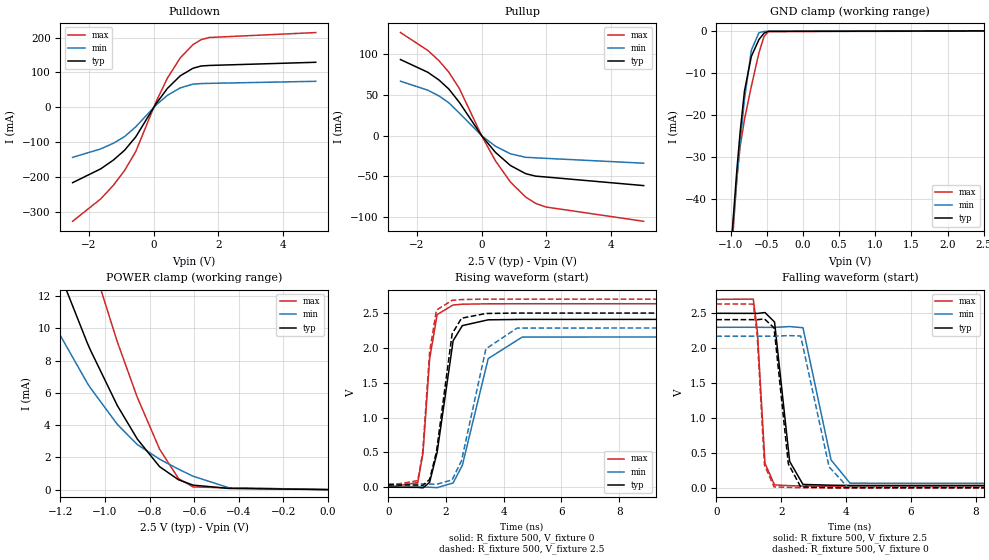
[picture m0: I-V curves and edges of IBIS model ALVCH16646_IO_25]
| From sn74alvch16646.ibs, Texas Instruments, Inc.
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[Model]   ALVCH16646_IO_25
Model_type  I/O
Vinl=0.7
Vinh=1.7
Enable   Active-Low
Vref =   0
Rref =   500
Cref =   30p
Vmeas =   1.25
| variable   typ   min   max
C_comp   8.78pF   7.66pF   9.73pF
| C_pullup   9.93pF   8.26pF   10.92pF
| C_pulldown   13.09pF   9.52pF   17.04pF
| C_tri-state   8.78pF   7.66pF   9.73pF
[Temperature Range]   40   100   -40
| Ambient temperature   25   85   -40
[Voltage range]   2.5   2.3   2.7
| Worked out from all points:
|   slope of the pulldown table from 0 to 0.375 V, typ, clamps not added: 7.66 ohm
|   slope of the pullup table from 0 to 0.375 V, typ, clamps not added: 20.6 ohm
|   GND clamp passes 1 mA (typ) near -0.57 V on its own axis
|   POWER clamp passes 1 mA (typ) near -0.72 V on its own axis
|   rising waveform, R_fixture 500, V_fixture 0: 20-80 % time 455ps typ, 715ps min, 290ps max; typ from 0 V to 2.41 V
|   falling waveform, R_fixture 500, V_fixture 2.5: 20-80 % time 302ps typ, 501ps min, 182ps max; typ from 2.5 V to 0.034 V
|   rising waveform, R_fixture 500, V_fixture 2.5: 20-80 % time 425ps typ, 656ps min, 282ps max; typ from 0.034 V to 2.5 V
|   falling waveform, R_fixture 500, V_fixture 0: 20-80 % time 283ps typ, 486ps min, 176ps max; typ from 2.41 V to 0 V
[GND Clamp]
| ALVCH16646_IO_25
|   Voltage   I(typ)   I(min)   I(max)
-2.5V     -463.5mA   -424.7mA   -524.1mA
-1.085V   -72.18mA   -71.04mA   -77.61mA
-1.065V   -67.29mA   -66.6mA    -72.07mA
-1.05V    -63.66mA   -63.3mA    -67.97mA
-915mV    -32.94mA   -35.07mA   -34.9mA
-870mV    -24.02mA   -26.5mA    -27.39mA
-810mV    -14.27mA   -16.21mA   -21mA
-715mV    -6.042mA   -4.584mA   -13.14mA
-610mV    -2.066mA   -435.3uA   -5.208mA
-540mV    -534.1uA   -124.2uA   -1.331mA
-480mV    -113uA     -83.4uA    -159.8uA
2.5V      87.97pA    20.8uA     -42.68uA
[POWER Clamp]
| ALVCH16646_IO_25
|   Voltage   I(typ)   I(min)   I(max)
-2.5V     78.71mA    58.49mA    109mA
-1.385V   20.48mA    14.69mA    31.36mA
-1.24V    14.7mA     10.52mA    23.24mA
-1.08V    9.114mA    6.62mA     15.15mA
-1.065V   8.641mA    6.299mA    14.44mA
-945mV    5.218mA    4.051mA    9.173mA
-855mV    3.133mA    2.791mA    5.716mA
-755mV    1.42mA     1.885mA    2.505mA
-670mV    609.2uA    1.265mA    681.5uA
-605mV    277uA      830.7uA    166.5uA
-445mV    73.42uA    118.1uA    104.1uA
-31.15fV  87.97pA    322.4pA    50.89pA
[Pulldown]
| ALVCH16646_IO_25
|   Voltage   I(typ)   I(min)   I(max)
-2.5V     -215.2mA   -142.8mA   -325.7mA
-1.635V   -175.8mA   -118.7mA   -261.9mA
-1.24V    -150.4mA   -102.3mA   -222.4mA
-895mV    -122.3mA   -83.19mA   -180.2mA
-550mV    -83.96mA   -55.21mA   -125.8mA
70mV      10.13mA    6.566mA    15.4mA
425mV     54.54mA    34.7mA     83.99mA
820mV     90.47mA    55.98mA    141.7mA
1.215V    112.2mA    66.71mA    179.9mA
1.465V    118.6mA    68.28mA    193.9mA
1.715V    120.1mA    68.87mA    200.1mA
5V        129.2mA    74.77mA    214.2mA
[Pullup]
| ALVCH16646_IO_25
|   Voltage   I(typ)   I(min)   I(max)
-2.5V     92.96mA    66.45mA    126mA
-1.66V    77.48mA    55.56mA    104.2mA
-1.315V   68.02mA    48.56mA    91.64mA
-1.01V    56.98mA    40.11mA    77.55mA
-685mV    40.61mA    27.47mA    57.59mA
15mV      -812.9uA   -531.7uA   -1.2mA
425mV     -20.36mA   -12.93mA   -30.68mA
890mV     -36.57mA   -22.24mA   -56.75mA
1.36V     -46.54mA   -26.55mA   -75.17mA
1.67V     -49.6mA    -27.19mA   -82.95mA
1.985V    -50.63mA   -27.82mA   -87.32mA
5V        -61.14mA   -33.76mA   -104.8mA
[Ramp]
| ALVCH16646_IO_25
| variable   typ   min   max
dV/dt_r   1.45/4.71E-10   1.31/7.46E-10   1.59/3.02E-10
dV/dt_f   1.50/3.25E-10   1.37/5.36E-10   1.62/1.88E-10
R_load = 500
[Rising Waveform]
| ALVCH16646_IO_25
R_fixture =   500
C_fixture =   0
L_fixture =   0
V_fixture =   0
V_fixture_min = 0
V_fixture_max = 0
|   Time   V(typ)   V(min)   V(max)
0s        28.15uV    61.98uV    14.35uV
1.02ns    -2.027mV   1.242mV    67.66mV
1.2ns     -9.088mV   1.562mV    493mV
1.43ns    71.39mV    -361.3uV   1.84V
1.69ns    501mV      -5.697mV   2.478V
2.245ns   2.103V     61.29mV    2.616V
2.565ns   2.32V      316.2mV    2.627V
3.46ns    2.403V     1.846V     2.633V
4.635ns   2.409V     2.155V     2.634V
49.99ns   2.409V     2.172V     2.633V
[Falling Waveform]
| ALVCH16646_IO_25
R_fixture =   500
C_fixture =   0
L_fixture =   0
V_fixture =   2.5
V_fixture_min = 2.3
V_fixture_max = 2.7
|   Time   V(typ)   V(min)   V(max)
0s        2.5V       2.3V       2.7V
1.14ns    2.499V     2.3V       2.703V
1.265ns   2.498V     2.3V       2.25V
1.5ns     2.511V     2.299V     351.5mV
1.795ns   2.375V     2.298V     41.61mV
2.26ns    379mV      2.31V      31.5mV
2.67ns    49.29mV    2.294V     26.35mV
3.535ns   37.82mV    400.8mV    24.2mV
4.12ns    34.7mV     66.68mV    24.02mV
49.99ns   33.75mV    47.74mV    24.02mV
[Rising Waveform]
| ALVCH16646_IO_25
R_fixture =   500
C_fixture =   0
L_fixture =   0
V_fixture =   2.5
V_fixture_min = 2.3
V_fixture_max = 2.7
|   Time   V(typ)   V(min)   V(max)
0s        33.68mV    47.62mV    23.97mV
1.02ns    30.83mV    48.2mV     94.68mV
1.19ns    25.06mV    48.07mV    500.9mV
1.43ns    111.6mV    45.63mV    1.942V
1.665ns   505.5mV    41.32mV    2.542V
2.21ns    2.202V     105.2mV    2.683V
2.535ns   2.426V     381.1mV    2.694V
3.38ns    2.494V     1.986V     2.7V
4.46ns    2.5V       2.284V     2.7V
49.99ns   2.5V       2.3V       2.7V
[Falling Waveform]
| ALVCH16646_IO_25
R_fixture =   500
C_fixture =   0
L_fixture =   0
V_fixture =   0
V_fixture_min = 0
V_fixture_max = 0
|   Time   V(typ)   V(min)   V(max)
0s        2.409V     2.172V     2.633V
1.14ns    2.409V     2.172V     2.632V
1.26ns    2.408V     2.172V     2.188V
1.485ns   2.419V     2.172V     327.1mV
1.78ns    2.292V     2.172V     14.05mV
2.22ns    343.3mV    2.181V     7.067mV
2.6ns     14.18mV    2.175V     2.387mV
3.475ns   3.558mV    300.9mV    185.3uV
4.045ns   947.8uV    11.58mV    29.07uV
49.99ns   34.81uV    75.69uV    18.23uV
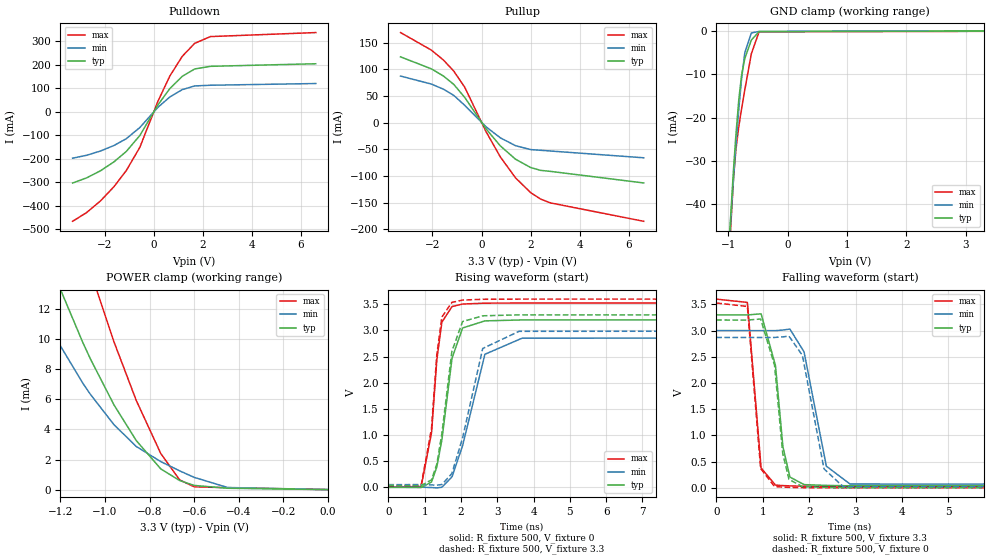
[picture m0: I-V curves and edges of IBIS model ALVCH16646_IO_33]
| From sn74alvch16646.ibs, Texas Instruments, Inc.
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[Model]   ALVCH16646_IO_33
Model_type  I/O
Vinl=0.8
Vinh=2.0
Enable   Active-Low
Vref =   0
Rref =   500
Cref =   50p
Vmeas =   1.5
| variable   typ   min   max
C_comp   8.55pF   7.36pF   9.71pF
| C_pullup   9.73pF   7.94pF   10.64pF
| C_pulldown   12.77pF   8.48pF   17.15pF
| C_tri-state   8.55pF   7.36pF   9.71pF
[Temperature Range]   40   100   -40
| Ambient temperature   25   85   -40
[Voltage range]   3.3   3   3.6
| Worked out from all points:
|   slope of the pulldown table from 0 to 0.495 V, typ, clamps not added: 6.36 ohm
|   slope of the pullup table from 0 to 0.495 V, typ, clamps not added: 16.5 ohm
|   GND clamp passes 1 mA (typ) near -0.56 V on its own axis
|   POWER clamp passes 1 mA (typ) near -0.72 V on its own axis
|   rising waveform, R_fixture 500, V_fixture 0: 20-80 % time 366ps typ, 530ps min, 252ps max; typ from 0 V to 3.2 V
|   falling waveform, R_fixture 500, V_fixture 3.3: 20-80 % time 216ps typ, 352ps min, 150ps max; typ from 3.3 V to 0.037 V
|   rising waveform, R_fixture 500, V_fixture 3.3: 20-80 % time 357ps typ, 504ps min, 249ps max; typ from 0.037 V to 3.3 V
|   falling waveform, R_fixture 500, V_fixture 0: 20-80 % time 208ps typ, 335ps min, 147ps max; typ from 3.2 V to 0 V
[GND Clamp]
| ALVCH16646_IO_33
|   Voltage   I(typ)   I(min)   I(max)
-3.3V     -697.1mA   -635.6mA   -790.9mA
-1.08V    -71.01mA   -69.96mA   -76.29mA
-1.06V    -66.13mA   -65.53mA   -70.76mA
-1.04V    -61.3mA    -61.15mA   -65.33mA
-910mV    -31.95mA   -34.12mA   -33.99mA
-870mV    -24.06mA   -26.53mA   -27.45mA
-820mV    -15.7mA    -17.84mA   -21.96mA
-775mV    -10.28mA   -11.12mA   -18.04mA
-720mV    -6.339mA   -5.024mA   -13.58mA
-610mV    -2.096mA   -458uA     -5.25mA
-480mV    -137.7uA   -101.7uA   -193.7uA
3.3V      119.8pA    41.63uA    -79.23uA
[POWER Clamp]
| ALVCH16646_IO_33
|   Voltage   I(typ)   I(min)   I(max)
-3.3V     128.4mA    96.51mA    173.7mA
-1.385V   20.52mA    14.71mA    31.41mA
-1.235V   14.54mA    10.41mA    23.02mA
-1.1V     9.791mA    7.084mA    16.15mA
-1.065V   8.672mA    6.321mA    14.48mA
-960mV    5.636mA    4.319mA    9.831mA
-860mV    3.263mA    2.869mA    5.931mA
-750mV    1.378mA    1.864mA    2.4mA
-665mV    600.8uA    1.246mA    642.9uA
-600mV    278.6uA    814uA      185.8uA
-450mV    90.53uA    139.8uA    126uA
-48.03fV  119.8pA    365.7pA    68.2pA
[Pulldown]
| ALVCH16646_IO_33
|   Voltage   I(typ)   I(min)   I(max)
-3.3V     -302.9mA   -197.2mA   -465.9mA
-2.735V   -281.2mA   -184.9mA   -429mA
-2.165V   -250.8mA   -166.7mA   -379.1mA
-1.615V   -212.7mA   -143mA     -318.3mA
-1.115V   -168.5mA   -114.3mA   -249.9mA
-565mV    -100.8mA   -66.68mA   -151.3mA
180mV     30.62mA    19.99mA    46.54mA
660mV     99.39mA    63.73mA    152.9mA
1.165V    151.5mA    94.78mA    236.7mA
1.67V     182.8mA    110.5mA    291.9mA
2.31V     194mA      113.5mA    320.7mA
6.6V      205mA      120.8mA    337.8mA
[Pullup]
| ALVCH16646_IO_33
|   Voltage   I(typ)   I(min)   I(max)
-3.3V     123.5mA    87.44mA    169.1mA
-2.045V   101mA      72.4mA     136.2mA
-1.55V    87.39mA    62.74mA    117.4mA
-1.13V    71.66mA    51.07mA    96.68mA
-685mV    47.27mA    32.42mA    66.38mA
180mV     -11.59mA   -7.766mA   -16.76mA
760mV     -43.54mA   -28.44mA   -64.12mA
1.38V     -68.63mA   -43.29mA   -103.6mA
2V        -84.39mA   -50.65mA   -131.6mA
2.405V    -89.66mA   -51.96mA   -143.6mA
2.81V     -91.58mA   -53.32mA   -150.8mA
6.6V      -113.3mA   -66.05mA   -185.3mA
[Ramp]
| ALVCH16646_IO_33
| variable   typ   min   max
dV/dt_r   1.93/3.84E-10   1.73/5.53E-10   2.12/2.57E-10
dV/dt_f   1.97/2.26E-10   1.79/3.68E-10   2.16/1.58E-10
R_load = 500
[Rising Waveform]
| ALVCH16646_IO_33
R_fixture =   500
C_fixture =   0
L_fixture =   0
V_fixture =   0
V_fixture_min = 0
V_fixture_max = 0
|   Time   V(typ)   V(min)   V(max)
0s        20.43uV    39.97uV    12.66uV
905ps     -4.37mV    2.377mV    17.4mV
1.19ns    103.1mV    -4.425mV   1.047V
1.335ns   388.8mV    -10.22mV   2.437V
1.475ns   910.7mV    1.208mV    3.161V
1.755ns   2.471V     202.1mV    3.458V
2.045ns   3.048V     795.4mV    3.506V
2.66ns    3.184V     2.545V     3.523V
3.685ns   3.202V     2.853V     3.526V
49.99ns   3.202V     2.869V     3.526V
[Falling Waveform]
| ALVCH16646_IO_33
R_fixture =   500
C_fixture =   0
L_fixture =   0
V_fixture =   3.3
V_fixture_min = 3
V_fixture_max = 3.6
|   Time   V(typ)   V(min)   V(max)
0s        3.3V       3V         3.6V
670ps     3.298V     3V         3.537V
965ps     3.32V      2.999V     379.1mV
1.275ns   2.332V     2.999V     52.42mV
1.435ns   783.7mV    3.01V      43.5mV
1.585ns   206.4mV    3.029V     37.37mV
1.89ns    61.82mV    2.595V     30.96mV
2.37ns    46.7mV     414mV      27.77mV
2.88ns    39.73mV    73.77mV    27.03mV
49.99ns   37.08mV    51.33mV    26.73mV
[Rising Waveform]
| ALVCH16646_IO_33
R_fixture =   500
C_fixture =   0
L_fixture =   0
V_fixture =   3.3
V_fixture_min = 3
V_fixture_max = 3.6
|   Time   V(typ)   V(min)   V(max)
0s        37.03mV    51.24mV    26.7mV
905ps     32mV       52.96mV    44.9mV
1.19ns    144.5mV    45.58mV    1.132V
1.335ns   444.9mV    40.58mV    2.54V
1.475ns   1.03V      54.2mV     3.258V
1.75ns    2.601V     264.1mV    3.537V
2.045ns   3.171V     945.6mV    3.582V
2.6ns     3.281V     2.656V     3.597V
3.6ns     3.299V     2.984V     3.6V
49.99ns   3.3V       3V         3.6V
[Falling Waveform]
| ALVCH16646_IO_33
R_fixture =   500
C_fixture =   0
L_fixture =   0
V_fixture =   0
V_fixture_min = 0
V_fixture_max = 0
|   Time   V(typ)   V(min)   V(max)
0s        3.202V     2.869V     3.526V
670ps     3.201V     2.869V     3.46V
955ps     3.221V     2.868V     367.7mV
1.255ns   2.338V     2.869V     24.82mV
1.43ns    661.9mV    2.88V      15.31mV
1.565ns   162.3mV    2.894V     9.93mV
1.855ns   22.83mV    2.527V     3.955mV
2.32ns    9.03mV     361.8mV    979.8uV
2.735ns   3.087mV    21.48mV    349.9uV
49.99ns   26.48uV    51.35uV    13.14uV
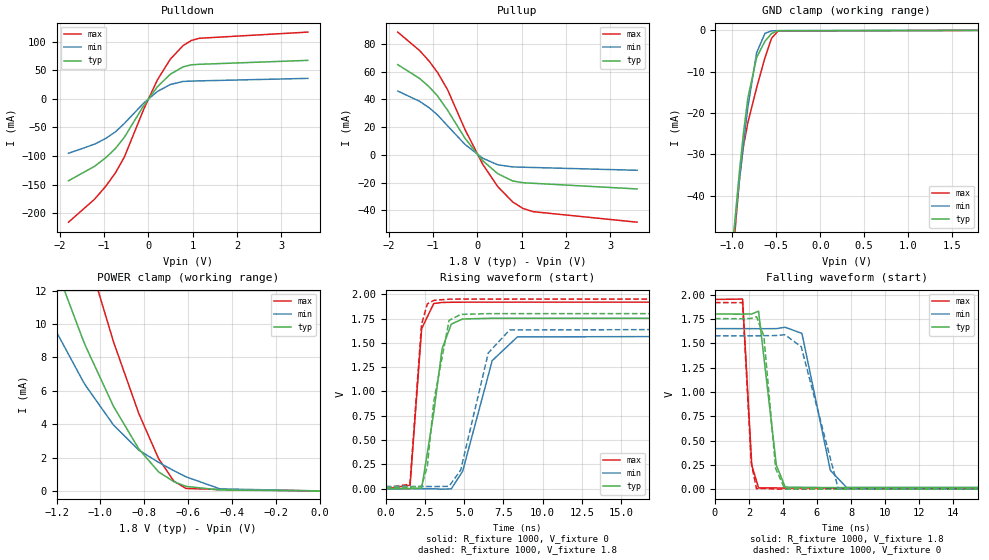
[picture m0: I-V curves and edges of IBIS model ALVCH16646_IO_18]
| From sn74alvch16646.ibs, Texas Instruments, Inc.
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[Model]   ALVCH16646_IO_18
Model_type  I/O
Vinl=0.5775
Vinh=1.2675
Enable   Active-Low
Vref =   0
Rref =   1000
Cref =   30p
Vmeas =   0.9
| variable   typ   min   max
C_comp   9.01pF   7.98pF   9.80pF
| C_pullup   10.08pF   8.45pF   10.94pF
| C_pulldown   13.56pF   10.24pF   17.53pF
| C_tri-state   9.01pF   7.98pF   9.80pF
[Temperature Range]   40   100   -40
| Ambient temperature   25   85   -40
[Voltage range]   1.8   1.65   1.95
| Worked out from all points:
|   slope of the pulldown table from 0 to 0.27 V, typ, clamps not added: 10.2 ohm
|   slope of the pullup table from 0 to 0.27 V, typ, clamps not added: 30.2 ohm
|   GND clamp passes 1 mA (typ) near -0.57 V on its own axis
|   POWER clamp passes 1 mA (typ) near -0.72 V on its own axis
|   rising waveform, R_fixture 1000, V_fixture 0: 20-80 % time 759ps typ, 1.5ns min, 427ps max; typ from 0 V to 1.75 V
|   falling waveform, R_fixture 1000, V_fixture 1.8: 20-80 % time 505ps typ, 1.03ns min, 289ps max; typ from 1.8 V to 0.016 V
|   rising waveform, R_fixture 1000, V_fixture 1.8: 20-80 % time 722ps typ, 1.36ns min, 417ps max; typ from 0.016 V to 1.8 V
|   falling waveform, R_fixture 1000, V_fixture 0: 20-80 % time 483ps typ, 972ps min, 281ps max; typ from 1.75 V to 0 V
[GND Clamp]
| ALVCH16646_IO_18
|   Voltage   I(typ)   I(min)   I(max)
-1.8V     -263.6mA   -244.1mA   -296.1mA
-1.085V   -72.13mA   -71mA      -77.54mA
-1.07V    -68.46mA   -67.66mA   -73.38mA
-1.055V   -64.81mA   -64.36mA   -69.26mA
-920mV    -33.94mA   -36.02mA   -35.84mA
-875mV    -24.91mA   -27.39mA   -28.02mA
-825mV    -16.36mA   -18.6mA    -22.32mA
-725mV    -6.538mA   -5.406mA   -13.88mA
-630mV    -2.629mA   -716.4uA   -6.604mA
-555mV    -750.6uA   -121.3uA   -1.917mA
-480mV    -86.02uA   -62.73uA   -123.2uA
1.8V      63.54pA    9.524uA    -22.72uA
[POWER Clamp]
| ALVCH16646_IO_18
|   Voltage   I(typ)   I(min)   I(max)
-1.8V     39.84mA    29.03mA    57.62mA
-1.39V    20.65mA    14.81mA    31.6mA
-1.245V   14.85mA    10.62mA    23.46mA
-1.08V    9.08mA     6.594mA    15.11mA
-1.065V   8.608mA    6.273mA    14.4mA
-940mV    5.06mA     3.946mA    8.929mA
-825mV    2.518mA    2.444mA    4.637mA
-735mV    1.142mA    1.715mA    1.939mA
-665mV    553.8uA    1.212mA    582uA
-610mV    273.2uA    844.7uA    148.5uA
-455mV    56.6uA     123.1uA    83uA
-16.28fV  63.54pA    285.4pA    36.64pA
[Pulldown]
| ALVCH16646_IO_18
|   Voltage   I(typ)   I(min)   I(max)
-1.8V     -143.3mA   -95.31mA   -215.7mA
-1.215V   -118.2mA   -79.49mA   -175.8mA
-960mV    -103.1mA   -69.37mA   -153mA
-735mV    -86.41mA   -57.44mA   -128.7mA
-540mV    -67.31mA   -43.13mA   -101.9mA
-100mV    -11.54mA   -7.259mA   -17.83mA
205mV     20.87mA    12.65mA    32.89mA
495mV     42.75mA    24.8mA     68.98mA
785mV     55.72mA    30.25mA    92.88mA
970mV     59.35mA    30.84mA    101.8mA
1.155V    60.2mA     31.26mA    105.7mA
3.6V      67.09mA    35.62mA    116.5mA
[Pullup]
| ALVCH16646_IO_18
|   Voltage   I(typ)   I(min)   I(max)
-1.8V     64.98mA    45.95mA    88.4mA
-1.305V   54.98mA    38.53mA    75.09mA
-1.09V    48.97mA    33.9mA     67.43mA
-900mV    42.35mA    28.69mA    59.27mA
-675mV    32.13mA    20.88mA    46.91mA
-280mV    11.84mA    7.43mA     18.08mA
120mV     -4.3mA     -2.474mA   -6.918mA
455mV     -13.55mA   -7.178mA   -22.84mA
795mV     -18.85mA   -8.713mA   -33.97mA
1.025V    -20.11mA   -8.923mA   -38.62mA
1.255V    -20.5mA    -9.129mA   -40.95mA
3.6V      -24.58mA   -11.14mA   -48.53mA
[Ramp]
| ALVCH16646_IO_18
| variable   typ   min   max
dV/dt_r   1.06/7.94E-10   0.95/1.57E-09   1.16/4.50E-10
dV/dt_f   1.09/5.58E-10   1.00/1.08E-09   1.18/3.11E-10
R_load = 1000
[Rising Waveform]
| ALVCH16646_IO_18
R_fixture =   1000
C_fixture =   0
L_fixture =   0
V_fixture =   0
V_fixture_min = 0
V_fixture_max = 0
|   Time   V(typ)   V(min)   V(max)
0s        62uV       110.2uV    35.07uV
1.55ns    623.7uV    817.1uV    35.64mV
2.29ns    5.961mV    415uV      1.647V
3.06ns    781.3mV    -689uV     1.904V
3.59ns    1.439V     -4.787mV   1.915V
4.18ns    1.693V     -1.649mV   1.917V
4.905ns   1.745V     181.1mV    1.918V
6.785ns   1.753V     1.317V     1.918V
8.39ns    1.753V     1.561V     1.918V
49.99ns   1.753V     1.576V     1.918V
[Falling Waveform]
| ALVCH16646_IO_18
R_fixture =   1000
C_fixture =   0
L_fixture =   0
V_fixture =   1.8
V_fixture_min = 1.65
V_fixture_max = 1.95
|   Time   V(typ)   V(min)   V(max)
0s        1.8V       1.65V      1.95V
1.625ns   1.799V     1.65V      1.954V
2.165ns   1.801V     1.65V      245.5mV
2.565ns   1.829V     1.649V     12.7mV
3.61ns    245.2mV    1.65V      12.48mV
4.13ns    21.22mV    1.664V     11.42mV
5.115ns   18.96mV    1.601V     11.08mV
6.785ns   15.98mV    193.2mV    11.08mV
7.74ns    15.88mV    17.07mV    11.09mV
49.99ns   16mV       23.68mV    11.13mV
[Rising Waveform]
| ALVCH16646_IO_18
R_fixture =   1000
C_fixture =   0
L_fixture =   0
V_fixture =   1.8
V_fixture_min = 1.65
V_fixture_max = 1.95
|   Time   V(typ)   V(min)   V(max)
0s        15.96mV    23.6mV     11.1mV
1.545ns   15.94mV    24.01mV    45.94mV
2.28ns    23.23mV    23.06mV    1.688V
2.65ns    231.7mV    22.84mV    1.9V
3.07ns    904.1mV    21.66mV    1.937V
4.035ns   1.73V      24.56mV    1.949V
4.775ns   1.792V     190.8mV    1.95V
6.535ns   1.8V       1.396V     1.95V
7.895ns   1.8V       1.632V     1.95V
49.99ns   1.8V       1.65V      1.95V
[Falling Waveform]
| ALVCH16646_IO_18
R_fixture =   1000
C_fixture =   0
L_fixture =   0
V_fixture =   0
V_fixture_min = 0
V_fixture_max = 0
|   Time   V(typ)   V(min)   V(max)
0s        1.753V     1.576V     1.918V
1.625ns   1.752V     1.576V     1.917V
2.135ns   1.755V     1.576V     269.9mV
2.445ns   1.773V     1.576V     3.31mV
2.875ns   1.573V     1.577V     6.634mV
3.57ns    212.6mV    1.579V     1.292mV
4.11ns    900.9uV    1.587V     252.9uV
5.07ns    2.409mV    1.465V     -8.78uV
7.255ns   -72.01uV   1.506mV    -10.98uV
49.99ns   64.79uV    112.4uV    35.74uV
